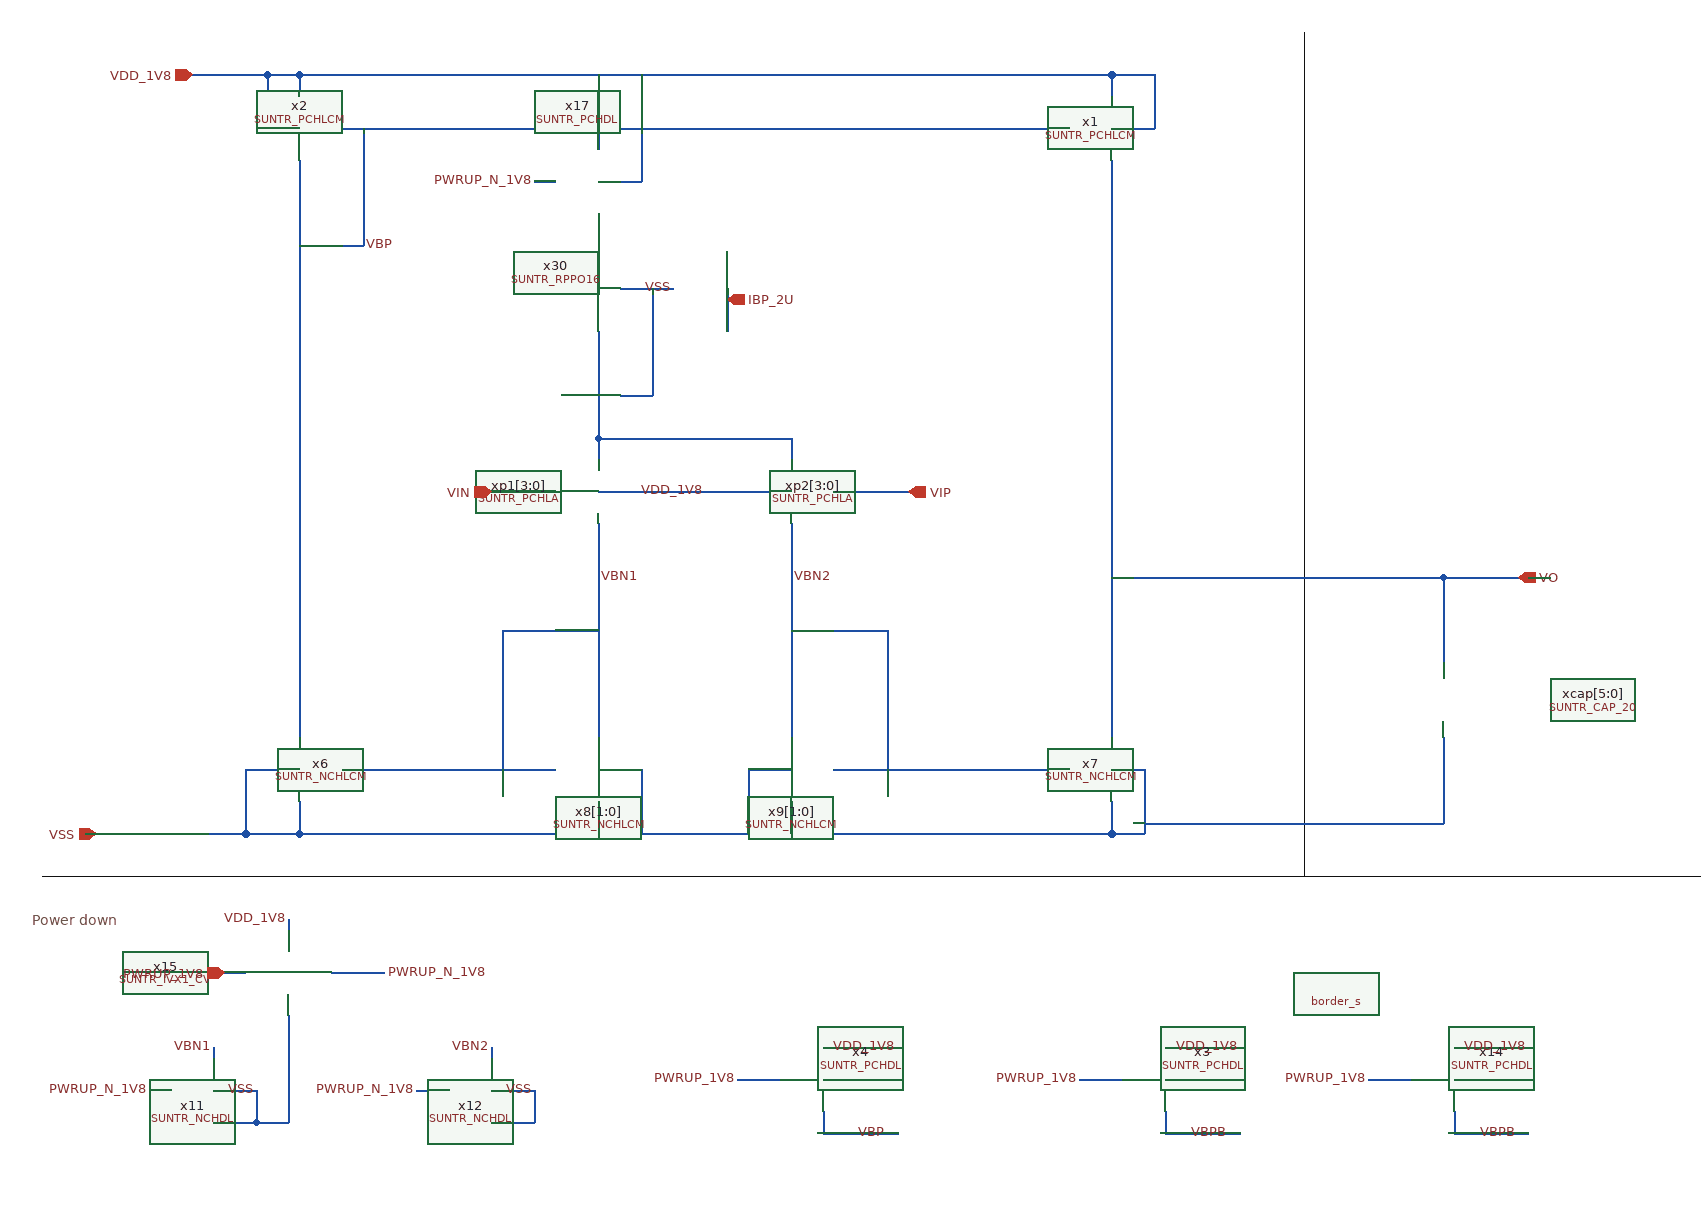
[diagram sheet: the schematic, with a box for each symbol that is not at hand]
v {xschem version=3.1.0 file_version=1.2 }
G {}
K {}
V {}
S {}
E {}
L 3 -810 -590 840 -590 {}
L 3 370 -1380 370 -590 {}
T {Power down } -820 -560 0 0 0.4 0.4 {}
N -290 -920 -290 -720 {
lab=VBN1}
N -110 -920 -110 -720 {
lab=VBN2}
N -290 -660 -290 -630 {
lab=VSS}
N -290 -630 190 -630 {
lab=VSS}
N 190 -660 190 -630 {
lab=VSS}
N -70 -690 150 -690 {
lab=VBN2}
N -110 -660 -110 -630 {
lab=VSS}
N -570 -660 -570 -630 {
lab=VSS}
N -570 -630 -290 -630 {
lab=VSS}
N -620 -690 -570 -690 {
lab=VSS}
N -620 -690 -620 -630 {
lab=VSS}
N -620 -630 -570 -630 {
lab=VSS}
N -530 -690 -330 -690 {
lab=VBN1}
N -380 -820 -290 -820 {
lab=VBN1}
N -380 -820 -380 -690 {
lab=VBN1}
N -110 -820 -20 -820 {
lab=VBN2}
N -20 -820 -20 -690 {
lab=VBN2}
N -460 -390 -430 -390 {
lab=PWRUP_N_1V8}
N -710 -390 -690 -390 {
lab=PWRUP_N_1V8}
N -290 -1000 -290 -980 {
lab=IBP_2U}
N -290 -1000 -110 -1000 {
lab=IBP_2U}
N -110 -1000 -110 -980 {
lab=IBP_2U}
N -290 -950 -110 -950 {
lab=VDD_1V8}
N -570 -1260 -570 -720 {
lab=VBP}
N -530 -1290 150 -1290 {
lab=VBP}
N -570 -1340 -570 -1320 {
lab=VDD_1V8}
N -570 -1340 190 -1340 {
lab=VDD_1V8}
N 190 -1340 190 -1320 {
lab=VDD_1V8}
N 190 -1290 230 -1290 {
lab=VDD_1V8}
N 230 -1340 230 -1290 {
lab=VDD_1V8}
N 190 -1340 230 -1340 {
lab=VDD_1V8}
N -600 -1290 -570 -1290 {
lab=VDD_1V8}
N -600 -1340 -600 -1290 {
lab=VDD_1V8}
N -600 -1340 -570 -1340 {
lab=VDD_1V8}
N 190 -1260 190 -1240 {
lab=VO}
N -80 -400 -10 -400 {
lab=VDD_1V8}
N -80 -430 -10 -430 {
lab=VDD_1V8}
N -10 -430 -10 -400 {
lab=VDD_1V8}
N 190 -1240 190 -720 {
lab=VO}
N -160 -400 -120 -400 {
lab=PWRUP_1V8}
N -670 -1340 -600 -1340 {
lab=VDD_1V8}
N -570 -1180 -510 -1180 {
lab=VBP}
N -510 -1290 -510 -1180 {
lab=VBP}
N 190 -690 220 -690 {
lab=VSS}
N 220 -690 220 -630 {
lab=VSS}
N -150 -690 -110 -690 {
lab=VSS}
N -150 -690 -150 -630 {
lab=VSS}
N -290 -690 -250 -690 {
lab=VSS}
N -250 -690 -250 -630 {
lab=VSS}
N -770 -630 -620 -630 {
lab=VSS}
N -540 -500 -490 -500 {
lab=PWRUP_N_1V8}
N -650 -500 -620 -500 {
lab=PWRUP_1V8}
N -360 -950 -330 -950 {
lab=VIN}
N 190 -630 220 -630 {
lab=VSS}
N -650 -430 -650 -420 {
lab=VBN1}
N -390 -430 -390 -420 {
lab=VBN2}
N -650 -390 -610 -390 {
lab=VSS}
N -610 -390 -610 -360 {
lab=VSS}
N -650 -360 -610 -360 {
lab=VSS}
N -390 -390 -350 -390 {
lab=VSS}
N -350 -390 -350 -360 {
lab=VSS}
N -390 -360 -350 -360 {
lab=VSS}
N -80 -370 -80 -350 {
lab=VBP}
N -80 -350 -10 -350 {
lab=VBP}
N -400 -950 -370 -950 {
lab=VIN}
N -370 -950 -360 -950 {
lab=VIN}
N -30 -950 0 -950 {
lab=VIP}
N 240 -400 310 -400 {
lab=VDD_1V8}
N 240 -430 310 -430 {
lab=VDD_1V8}
N 310 -430 310 -400 {
lab=VDD_1V8}
N 160 -400 200 -400 {
lab=PWRUP_1V8}
N 240 -370 240 -350 {
lab=VBPB}
N 240 -350 310 -350 {
lab=VBPB}
N -70 -950 -30 -950 {
lab=VIP}
N -270 -1140 -220 -1140 {
lab=VSS}
N -290 -1210 -290 -1180 {
lab=#net1}
N -290 -1340 -290 -1270 {
lab=VDD_1V8}
N 510 -400 580 -400 {
lab=VDD_1V8}
N 510 -430 580 -430 {
lab=VDD_1V8}
N 580 -430 580 -400 {
lab=VDD_1V8}
N 430 -400 470 -400 {
lab=PWRUP_1V8}
N 510 -370 510 -350 {
lab=VBPB}
N 510 -350 580 -350 {
lab=VBPB}
N -290 -1240 -250 -1240 {
lab=VDD_1V8}
N -250 -1340 -250 -1240 {
lab=VDD_1V8}
N -350 -1240 -330 -1240 {
lab=PWRUP_N_1V8}
N -290 -1100 -290 -1080 {
lab=#net2}
N -580 -550 -580 -540 {
lab=VDD_1V8}
N -580 -460 -580 -360 {
lab=VSS}
N -610 -360 -580 -360 {
lab=VSS}
N 220 -640 500 -640 {
lab=VSS}
N 470 -870 500 -870 {
lab=VO}
N 500 -870 580 -870 {
lab=VO}
N 190 -870 390 -870 {
lab=VO}
N 390 -870 470 -870 {
lab=VO}
N -270 -1040 -240 -1040 {
lab=VSS}
N -240 -1140 -240 -1040 {
lab=VSS}
N -170 -1140 -170 -1100 {
lab=IBP_2U}
N 500 -720 500 -640 {
lab=VSS}
N 500 -870 500 -790 {
lab=VO}
N -290 -1080 -290 -1010 {}
N -290 -1010 -290 -1000 {}
C {cborder/border_s.sym} 400 -480 0 0 {}
C {SUN_TR_SKY130NM/SUNTR_PCHLCM.sym} 150 -1290 0 0 {name=x1  }
C {SUN_TR_SKY130NM/SUNTR_PCHLCM.sym} -530 -1290 0 1 {name=x2 }
C {SUN_TR_SKY130NM/SUNTR_PCHDL.sym} -120 -400 0 0 {name=x4  }
C {SUN_TR_SKY130NM/SUNTR_NCHLCM.sym} 150 -690 0 0 {name=x7  }
C {SUN_TR_SKY130NM/SUNTR_NCHLCM.sym} -530 -690 0 1 {name=x6  }
C {SUN_TR_SKY130NM/SUNTR_NCHLCM.sym} -330 -690 0 0 {name=x8[1:0]}
C {SUN_TR_SKY130NM/SUNTR_NCHLCM.sym} -70 -690 0 1 {name=x9[1:0]}
C {SUN_TR_SKY130NM/SUNTR_NCHDL.sym} -690 -390 0 0 {name=x11  }
C {SUN_TR_SKY130NM/SUNTR_NCHDL.sym} -430 -390 0 0 {name=x12  }
C {SUN_TR_SKY130NM/SUNTR_PCHLA.sym} -330 -950 0 0 {name=xp1[3:0] }
C {SUN_TR_SKY130NM/SUNTR_PCHLA.sym} -70 -950 0 1 {name=xp2[3:0]  }
C {devices/ipin.sym} -670 -1340 0 0 {name=p1 lab=VDD_1V8}
C {devices/lab_pin.sym} -510 -1180 0 1 {name=l2 sig_type=std_logic lab=VBP}
C {devices/opin.sym} 570 -870 0 0 {name=p2 lab=VO}
C {devices/lab_pin.sym} -160 -400 0 0 {name=l5 sig_type=std_logic lab=PWRUP_1V8}
C {devices/lab_pin.sym} -290 -870 0 1 {name=l6 sig_type=std_logic lab=VBN1}
C {devices/lab_pin.sym} -110 -870 0 1 {name=l7 sig_type=std_logic lab=VBN2}
C {devices/ipin.sym} -760 -630 0 0 {name=p3 lab=VSS}
C {SUN_TR_SKY130NM/SUNTR_IVX1_CV.sym} -620 -500 0 0 {name=x15  }
C {devices/ipin.sym} -640 -500 0 0 {name=p4 lab=PWRUP_1V8}
C {devices/lab_pin.sym} -490 -500 0 1 {name=l12 sig_type=std_logic lab=PWRUP_N_1V8}
C {devices/ipin.sym} -390 -950 0 0 {name=p5 lab=VIN}
C {devices/ipin.sym} 0 -950 0 1 {name=p6 lab=VIP}
C {devices/lab_wire.sym} -610 -390 0 0 {name=l3 sig_type=std_logic lab=VSS}
C {devices/lab_wire.sym} -710 -390 0 0 {name=l4 sig_type=std_logic lab=PWRUP_N_1V8}
C {devices/lab_wire.sym} -460 -390 0 0 {name=l18 sig_type=std_logic lab=PWRUP_N_1V8}
C {devices/lab_wire.sym} -650 -430 0 0 {name=l19 sig_type=std_logic lab=VBN1}
C {devices/lab_wire.sym} -390 -430 0 0 {name=l20 sig_type=std_logic lab=VBN2}
C {devices/lab_wire.sym} -350 -390 0 0 {name=l21 sig_type=std_logic lab=VSS}
C {devices/lab_wire.sym} -10 -430 0 0 {name=l22 sig_type=std_logic lab=VDD_1V8}
C {devices/lab_wire.sym} -20 -350 0 0 {name=l23 sig_type=std_logic lab=VBP}
C {devices/lab_wire.sym} -190 -950 0 0 {name=l24 sig_type=std_logic lab=VDD_1V8}
C {SUN_TR_SKY130NM/SUNTR_PCHDL.sym} 200 -400 0 0 {name=x3  }
C {devices/lab_pin.sym} 160 -400 0 0 {name=l31 sig_type=std_logic lab=PWRUP_1V8}
C {devices/lab_wire.sym} 310 -430 0 0 {name=l32 sig_type=std_logic lab=VDD_1V8}
C {devices/lab_wire.sym} 300 -350 0 0 {name=l33 sig_type=std_logic lab=VBPB}
C {devices/ipin.sym} -170 -1130 3 1 {name=p7 lab=IBP_2U}
C {SUN_TR_SKY130NM/SUNTR_RPPO16.sym} -290 -1180 3 1 {name=x30  }
C {devices/lab_wire.sym} -220 -1140 0 0 {name=l37 sig_type=std_logic lab=VSS}
C {devices/lab_wire.sym} -580 -550 0 0 {name=l1 sig_type=std_logic lab=VDD_1V8}
C {SUN_TR_SKY130NM/SUNTR_PCHDL.sym} 470 -400 0 0 {name=x14  }
C {devices/lab_pin.sym} 430 -400 0 0 {name=l10 sig_type=std_logic lab=PWRUP_1V8}
C {devices/lab_wire.sym} 580 -430 0 0 {name=l11 sig_type=std_logic lab=VDD_1V8}
C {devices/lab_wire.sym} 570 -350 0 0 {name=l14 sig_type=std_logic lab=VBPB}
C {SUN_TR_SKY130NM/SUNTR_PCHDL.sym} -330 -1240 0 0 {name=x17  }
C {devices/lab_pin.sym} -350 -1240 0 0 {name=l15 sig_type=std_logic lab=PWRUP_N_1V8}
C {SUN_TR_SKY130NM/SUNTR_CAP_20.sym} 500 -730 0 0 {name=xcap[5:0]}
